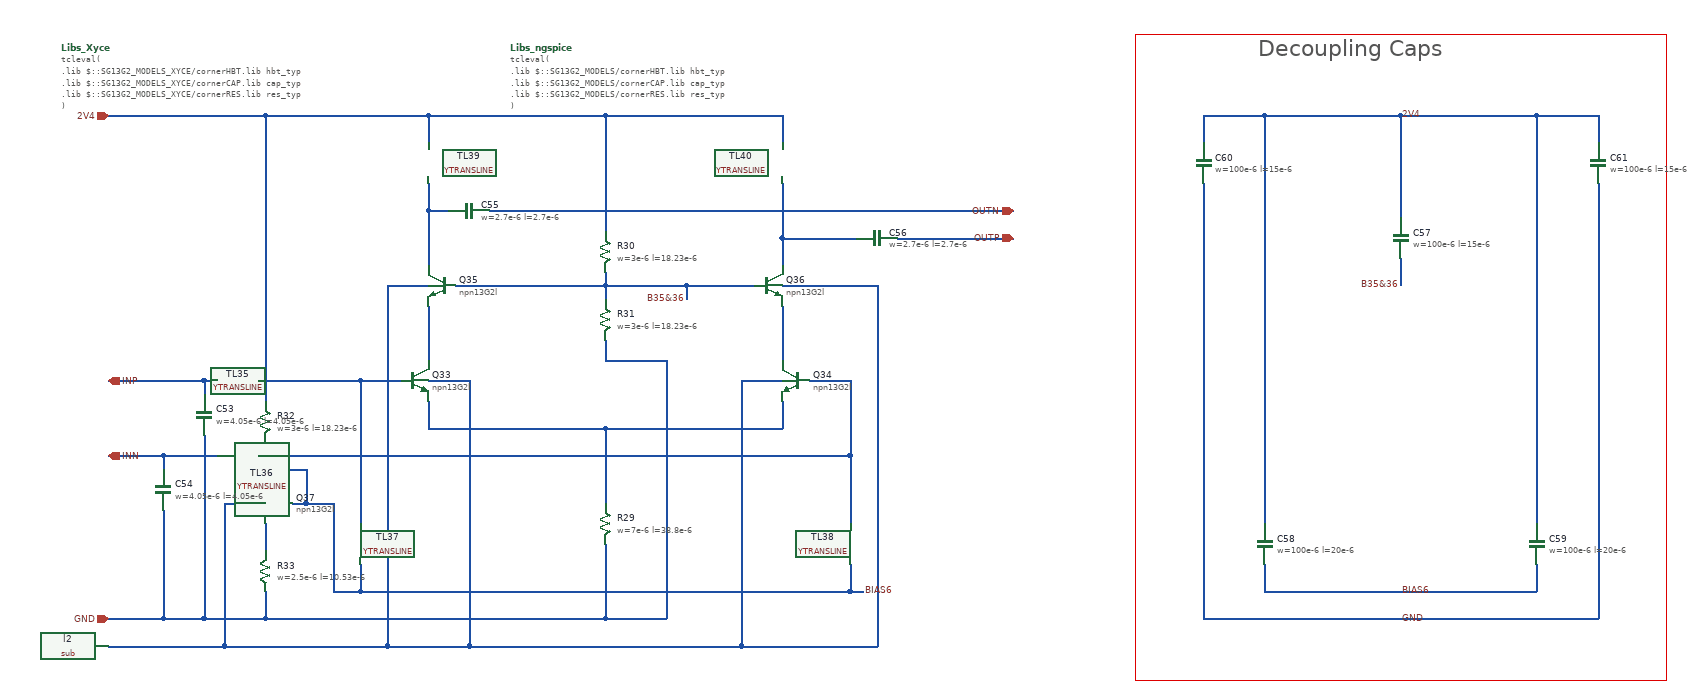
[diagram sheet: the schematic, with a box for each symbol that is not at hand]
v {xschem version=3.4.7 file_version=1.2}
G {}
K {}
V {}
S {}
E {}
L 7 1590 -980 2200 -980 {}
L 7 1590 -980 1590 -30 {}
L 7 1590 -30 2370 -30 {}
L 7 2370 -380 2370 -30 {}
L 7 2370 -980 2370 -380 {}
L 7 2160 -980 2370 -980 {}
T {Decoupling Caps} 1770 -970 0 0 1 1 {layer=7}
N 310 -340 370 -340 {lab=BIAS6}
N 350 -290 370 -290 {lab=BIAS6}
N 1110 -470 1170 -470 {lab=#net1}
N 310 -340 310 -320 {lab=BIAS6}
N 370 -340 370 -290 {lab=BIAS6}
N 310 -260 310 -220 {lab=#net2}
N 1070 -860 1070 -820 {lab=2V4}
N 550 -860 550 -820 {lab=2V4}
N 1070 -760 1070 -680 {lab=#net3}
N 1070 -440 1070 -400 {lab=#net4}
N 550 -440 550 -400 {lab=#net4}
N 550 -470 610 -470 {lab=sub!}
N 1010 -470 1070 -470 {lab=sub!}
N 250 -290 310 -290 {lab=sub!}
N 310 -380 310 -340 {lab=BIAS6}
N 310 -860 550 -860 {lab=2V4}
N 810 -400 810 -290 {lab=#net4}
N 1070 -680 1070 -640 {lab=#net3}
N 930 -610 1030 -610 {lab=B35&36}
N 1070 -580 1070 -500 {lab=#net5}
N 810 -630 810 -610 {lab=B35&36}
N 810 -860 810 -690 {lab=2V4}
N 310 -860 310 -440 {lab=2V4}
N 310 -160 310 -120 {lab=GND}
N 450 -200 450 -160 {lab=BIAS6}
N 1170 -200 1170 -160 {lab=BIAS6}
N 1170 -360 1170 -260 {lab=#net1}
N 1170 -160 1190 -160 {lab=BIAS6}
N 450 -160 1170 -160 {lab=BIAS6}
N 410 -160 450 -160 {lab=BIAS6}
N 410 -290 410 -160 {lab=BIAS6}
N 370 -290 410 -290 {lab=BIAS6}
N 220 -120 310 -120 {lab=GND}
N 810 -230 810 -120 {lab=GND}
N 490 -610 550 -610 {lab=sub!}
N 1070 -610 1210 -610 {lab=sub!}
N 220 -470 220 -450 {lab=INP}
N 220 -390 220 -120 {lab=GND}
N 160 -360 160 -340 {lab=INN}
N 220 -470 240 -470 {lab=INP}
N 300 -360 1170 -360 {lab=#net1}
N 1170 -470 1170 -360 {lab=#net1}
N 550 -720 580 -720 {lab=#net6}
N 640 -720 1410 -720 {lab=OUTN}
N 1240 -680 1410 -680 {lab=OUTP}
N 1070 -680 1180 -680 {lab=#net3}
N 80 -470 220 -470 {lab=INP}
N 160 -360 240 -360 {lab=INN}
N 80 -360 160 -360 {lab=INN}
N 160 -120 220 -120 {lab=GND}
N 80 -860 310 -860 {lab=2V4}
N 310 -120 810 -120 {lab=GND}
N 1010 -80 1210 -80 {lab=sub!}
N 1210 -610 1210 -80 {lab=sub!}
N 1010 -470 1010 -80 {lab=sub!}
N 610 -80 1010 -80 {lab=sub!}
N 610 -470 610 -80 {lab=sub!}
N 490 -80 610 -80 {lab=sub!}
N 490 -610 490 -80 {lab=sub!}
N 250 -290 250 -80 {lab=sub!}
N 250 -80 490 -80 {lab=sub!}
N 80 -80 250 -80 {lab=sub!}
N 930 -610 930 -590 {lab=B35&36}
N 590 -610 810 -610 {lab=B35&36}
N 300 -470 450 -470 {lab=#net7}
N 450 -470 450 -260 {lab=#net7}
N 80 -120 160 -120 {lab=GND}
N 810 -610 930 -610 {lab=B35&36}
N 810 -610 810 -590 {lab=B35&36}
N 810 -530 810 -500 {lab=GND}
N 810 -500 900 -500 {lab=GND}
N 900 -500 900 -120 {lab=GND}
N 810 -120 900 -120 {lab=GND}
N 550 -860 810 -860 {lab=2V4}
N 2270 -760 2270 -120 {lab=GND}
N 1690 -860 1690 -820 {lab=2V4}
N 2270 -860 2270 -820 {lab=2V4}
N 1780 -200 1780 -160 {lab=BIAS4}
N 2180 -200 2180 -160 {lab=BIAS4}
N 1980 -650 1980 -610 {lab=B35&36}
N 1980 -860 1980 -710 {lab=2V4}
N 2180 -860 2180 -260 {lab=2V4}
N 2180 -860 2270 -860 {lab=2V4}
N 1780 -860 1780 -260 {lab=2V4}
N 1690 -120 2270 -120 {lab=GND}
N 1690 -760 1690 -120 {lab=GND}
N 1780 -160 2180 -160 {lab=BIAS4}
N 1690 -860 1780 -860 {lab=2V4}
N 810 -400 1070 -400 {lab=#net4}
N 1780 -860 1980 -860 {lab=2V4}
N 1980 -860 2180 -860 {lab=2V4}
N 550 -720 550 -640 {lab=#net6}
N 550 -760 550 -720 {lab=#net6}
N 550 -580 550 -500 {lab=#net8}
N 550 -400 810 -400 {lab=#net4}
N 810 -860 1070 -860 {lab=2V4}
N 160 -280 160 -120 {lab=GND}
N 450 -470 510 -470 {lab=#net7}
C {sg13g2_pr/npn13G2l.sym} 530 -470 0 0 {name=Q33
model=npn13G2l
spiceprefix=X
Nx=4
El=2.5}
C {sg13g2_pr/npn13G2l.sym} 1090 -470 0 1 {name=Q34
model=npn13G2l
spiceprefix=X
Nx=4
El=2.5}
C {sg13g2_pr/npn13G2l.sym} 330 -290 0 1 {name=Q37
model=npn13G2l
spiceprefix=X
Nx=1
El=2.5}
C {lab_pin.sym} 1190 -160 0 1 {name=p8 sig_type=std_logic lab=BIAS6}
C {iopin.sym} 80 -860 2 0 {name=p1 lab=2V4}
C {iopin.sym} 80 -120 2 0 {name=p2 lab=GND}
C {iopin.sym} 1410 -720 0 0 {name=p4 lab=OUTN}
C {iopin.sym} 1410 -680 0 0 {name=p5 lab=OUTP}
C {title.sym} 160 -30 0 0 {name=l1 author="Ghaith AL SABAGH" lock=true}
C {sg13g2_pr/npn13G2l.sym} 570 -610 0 1 {name=Q35
model=npn13G2l
spiceprefix=X
Nx=4
El=2.5}
C {sg13g2_pr/npn13G2l.sym} 1050 -610 0 0 {name=Q36
model=npn13G2l
spiceprefix=X
Nx=4
El=2.5}
C {iopin.sym} 80 -470 0 1 {name=p3 lab=INP}
C {iopin.sym} 80 -360 0 1 {name=p10 lab=INN}
C {YTRANSLINE.sym} 450 -230 1 0 {name=TL37 R=22.16k L=445.9n C=61.5p len=30u lumps=50 Z0=85
}
C {YTRANSLINE.sym} 1170 -230 3 1 {name=TL38 R=22.16k L=445.9n C=61.5p len=30u lumps=50 Z0=85
}
C {YTRANSLINE.sym} 270 -470 2 0 {name=TL35 R=22.16k L=445.9n C=61.5p len=50u lumps=50 Z0=85
}
C {YTRANSLINE.sym} 270 -360 0 1 {name=TL36 R=22.16k L=445.9n C=61.5p len=50u lumps=50 Z0=85
}
C {YTRANSLINE.sym} 550 -790 1 0 {name=TL39 R=22.16k L=445.9n C=61.5p len=77.5u lumps=50 Z0=85
}
C {YTRANSLINE.sym} 1070 -790 3 1 {name=TL40 R=22.16k L=445.9n C=61.5p len=77.5u lumps=50 Z0=85
}
C {sg13g2_pr/rppd.sym} 310 -410 0 0 {name=R32
w=3e-6
l=18.23e-6
model=rppd
spiceprefix=X
b=0
m=2
}
C {simulator_commands_shown.sym} 10 -960 0 0 {name=Libs_Xyce
simulator=xyce
only_toplevel=false 
value="tcleval(
.lib $::SG13G2_MODELS_XYCE/cornerHBT.lib hbt_typ
.lib $::SG13G2_MODELS_XYCE/cornerCAP.lib cap_typ
.lib $::SG13G2_MODELS_XYCE/cornerRES.lib res_typ
)"}
C {simulator_commands_shown.sym} 670 -960 0 0 {name=Libs_ngspice
simulator=ngspice
only_toplevel=false 
value="tcleval(
.lib $::SG13G2_MODELS/cornerHBT.lib hbt_typ
.lib $::SG13G2_MODELS/cornerCAP.lib cap_typ
.lib $::SG13G2_MODELS/cornerRES.lib res_typ
)"}
C {sg13g2_pr/sub.sym} 80 -80 1 1 {name=l2 lab=sub!}
C {sg13g2_pr/cap_cmim.sym} 220 -420 0 1 {name=C53
model=cap_cmim
w=4.05e-6
l=4.05e-6
m=1
spiceprefix=X}
C {sg13g2_pr/cap_cmim.sym} 160 -310 0 1 {name=C54
model=cap_cmim
w=4.05e-6
l=4.05e-6
m=1
spiceprefix=X}
C {sg13g2_pr/cap_cmim.sym} 610 -720 1 1 {name=C55
model=cap_cmim
w=2.7e-6
l=2.7e-6
m=1
spiceprefix=X}
C {sg13g2_pr/cap_cmim.sym} 1210 -680 1 1 {name=C56
model=cap_cmim
w=2.7e-6
l=2.7e-6
m=1
spiceprefix=X}
C {lab_pin.sym} 930 -590 3 0 {name=p11 sig_type=std_logic lab=B35&36}
C {sg13g2_pr/rppd.sym} 310 -190 0 1 {name=R33
w=2.5e-6
l=10.53e-6
model=rppd
spiceprefix=X
b=0
m=14
}
C {sg13g2_pr/rppd.sym} 810 -660 0 0 {name=R30
w=3e-6
l=18.23e-6
model=rppd
spiceprefix=X
b=0
m=2
}
C {sg13g2_pr/rppd.sym} 810 -560 0 0 {name=R31
w=3e-6
l=18.23e-6
model=rppd
spiceprefix=X
b=0
m=1
}
C {sg13g2_pr/cap_cmim.sym} 1780 -230 0 1 {name=C58
model=cap_cmim
w=100e-6
l=20e-6
m=1
spiceprefix=X
}
C {sg13g2_pr/cap_cmim.sym} 1980 -680 0 1 {name=C57
model=cap_cmim
w=100e-6
l=15e-6
m=1
spiceprefix=X
}
C {sg13g2_pr/cap_cmim.sym} 2180 -230 0 0 {name=C59
model=cap_cmim
w=100e-6
l=20e-6
m=1
spiceprefix=X
}
C {sg13g2_pr/cap_cmim.sym} 1690 -790 0 1 {name=C60
model=cap_cmim
w=100e-6
l=15e-6
m=1
spiceprefix=X
}
C {sg13g2_pr/cap_cmim.sym} 2270 -790 0 0 {name=C61
model=cap_cmim
w=100e-6
l=15e-6
m=1
spiceprefix=X
}
C {lab_pin.sym} 1980 -610 3 0 {name=p12 sig_type=std_logic lab=B35&36
}
C {lab_wire.sym} 1980 -160 0 1 {name=p13 sig_type=std_logic lab=BIAS6}
C {lab_wire.sym} 1980 -860 0 1 {name=p14 sig_type=std_logic lab=2V4}
C {lab_wire.sym} 1980 -120 0 1 {name=p15 sig_type=std_logic lab=GND}
C {sg13g2_pr/rsil.sym} 810 -260 0 0 {name=R29
w=7e-6
l=38.8e-6
model=rsil
spiceprefix=X
b=0
m=4
}
